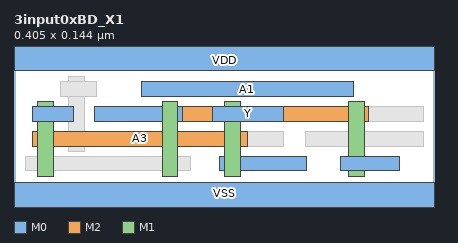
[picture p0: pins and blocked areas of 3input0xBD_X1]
MACRO 3input0xBD_X1
  CLASS CORE ;
  ORIGIN 0 0 ;
  FOREIGN 3input0xBD_X1 0 0 ;
  SIZE 0.4050 BY 0.1440 ;
  SYMMETRY X Y ;
  SITE coresite ;
  PIN A1
    DIRECTION INPUT ;
    USE SIGNAL ;
    PORT
      LAYER M0 ;
        RECT 0.1230 0.1010 0.3270 0.1150 ;
    END
  END A1
  PIN A2
    DIRECTION INPUT ;
    USE SIGNAL ;
    PORT
      LAYER M2 ;
        RECT 0.1350 0.0770 0.3420 0.0910 ;
      LAYER M1 ;
        RECT 0.1430 0.0240 0.1580 0.0960 ;
        RECT 0.3230 0.0240 0.3380 0.0960 ;
      LAYER M0 ;
        RECT 0.3150 0.0290 0.3720 0.0430 ;
        RECT 0.0780 0.0770 0.1620 0.0910 ;
    END
  END A2
  PIN A3
    DIRECTION INPUT ;
    USE SIGNAL ;
    PORT
      LAYER M2 ;
        RECT 0.0180 0.0530 0.2250 0.0670 ;
      LAYER M1 ;
        RECT 0.0230 0.0240 0.0380 0.0960 ;
        RECT 0.2030 0.0240 0.2180 0.0960 ;
      LAYER M0 ;
        RECT 0.1980 0.0290 0.2820 0.0430 ;
        RECT 0.0180 0.0770 0.0570 0.0910 ;
    END
  END A3
  PIN Y
    DIRECTION OUTPUT ;
    USE SIGNAL ;
    PORT
      LAYER M0 ;
        RECT 0.1910 0.0770 0.2600 0.0910 ;
    END
  END Y
  PIN VDD
    DIRECTION INOUT ;
    USE POWER ;
    SHAPE ABUTMENT ;
    PORT
      LAYER M0 ;
        RECT 0.0000 0.1260 0.4050 0.1620 ;
    END
  END VDD
  PIN VSS
    DIRECTION INOUT ;
    USE GROUND ;
    SHAPE ABUTMENT ;
    PORT
      LAYER M0 ;
        RECT 0.0000 -0.0180 0.4050 0.0180 ;
    END
  END VSS
  OBS
    LAYER V1 ;
      RECT 0.1430 0.0770 0.1570 0.0910 ;
      RECT 0.3230 0.0770 0.3370 0.0910 ;
      RECT 0.0230 0.0530 0.0370 0.0670 ;
      RECT 0.2030 0.0530 0.2170 0.0670 ;
    LAYER M1 ;
      RECT 0.0530 0.0480 0.0680 0.1200 ;
    LAYER V0 ;
      RECT 0.1430 0.0770 0.1570 0.0910 ;
      RECT 0.3230 0.0290 0.3370 0.0430 ;
      RECT 0.0230 0.0770 0.0370 0.0910 ;
      RECT 0.2030 0.0290 0.2170 0.0430 ;
      RECT 0.0530 0.1010 0.0670 0.1150 ;
      RECT 0.0530 0.0530 0.0670 0.0670 ;
    LAYER M0 ;
      RECT 0.0110 0.0290 0.1700 0.0430 ;
      RECT 0.0450 0.0530 0.2600 0.0670 ;
      RECT 0.2810 0.0530 0.3950 0.0670 ;
      RECT 0.2810 0.0770 0.3950 0.0910 ;
      RECT 0.0450 0.1010 0.0800 0.1150 ;
  END
END 3input0xBD_X1
